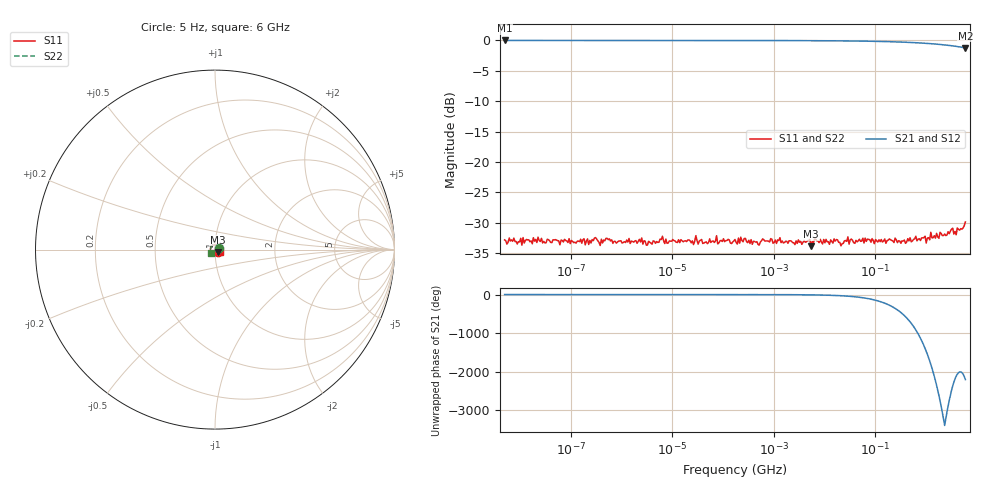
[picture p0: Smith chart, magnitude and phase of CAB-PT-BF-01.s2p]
! CAL-ELEKTRA — DATOS SINTÉTICOS DE EJEMPLO: no son una medida real.
! Cable simulado CAB-PT-BF-01: 1.0 m, 5 Hz – 6 GHz
# HZ S RI R 50
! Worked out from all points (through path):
!   401 points, 5 Hz to 6 GHz, reference 50 ohm
!   highest |S21| = 0.00 dB at 5 Hz (marker M1); lowest = -1.2 dB at 6 GHz (marker M2)
!   lowest |S11| = -33.8 dB at 5.453 MHz (marker M3), VSWR 1.04, Z = 51.6 - j1.36 ohm
!   |S11| at or under -10 dB: start of sweep to end of sweep
!   |S22| runs from -33.8 to -29.9 dB; largest |S21 - S12| = 0
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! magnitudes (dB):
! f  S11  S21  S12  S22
! 5 Hz  -32.8  0.0  0.0  -32.8
! 165.9 Hz  -33.4  0.0  0.0  -33.4
! 294.7 Hz  -32.5  0.0  0.0  -32.5
! 382.7 Hz  -33.7  0.0  0.0  -33.7
! 523.7 Hz  -32.6  0.0  0.0  -32.6
! 3.437 kHz  -33.0  0.0  0.0  -33.0
! 5.502 kHz  -33.2  0.0  0.0  -33.2
! 173.2 kHz  -32.7  0.0  0.0  -32.7
! 249.7 kHz  -33.1  0.0  0.0  -33.1
! 492.6 kHz  -33.6  0.0  0.0  -33.6
! 639.7 kHz  -32.8  0.0  0.0  -32.8
! 5.453 MHz  -33.8  0.0  0.0  -33.8
! 5.745 MHz  -33.1  0.0  0.0  -33.1
! 17.22 MHz  -32.7  -0.1  -0.1  -32.7
! 21.22 MHz  -33.8  -0.1  -0.1  -33.8
! 32.24 MHz  -32.8  -0.1  -0.1  -32.8
! 190.6 MHz  -32.7  -0.2  -0.2  -32.7
! 1.069 GHz  -32.5  -0.5  -0.5  -32.5
! 2.342 GHz  -31.8  -0.7  -0.7  -31.8
! 3.041 GHz  -31.4  -0.8  -0.8  -31.4
! 3.95 GHz  -32.0  -1.0  -1.0  -32.0
! 6 GHz  -29.9  -1.2  -1.2  -29.9
